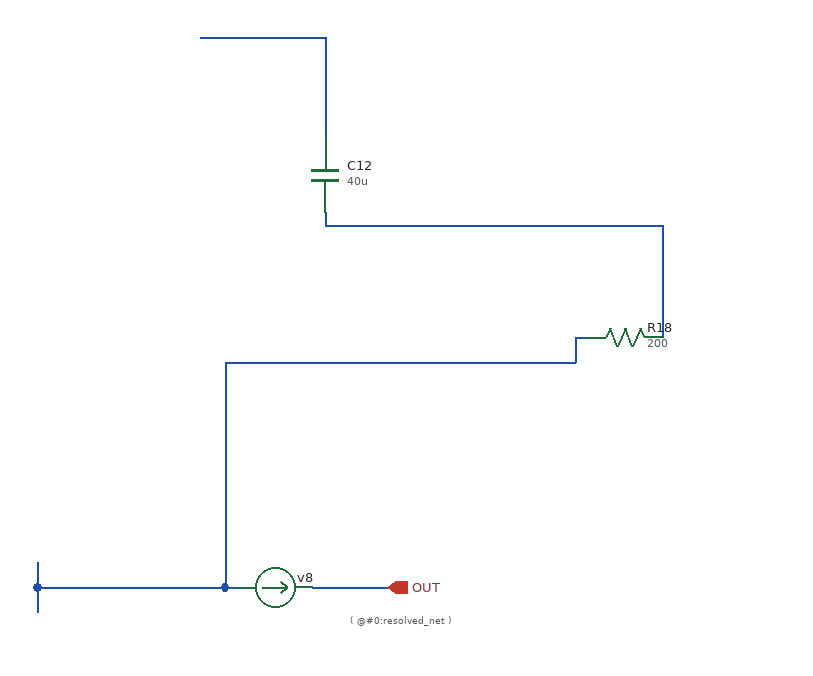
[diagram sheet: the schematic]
v {xschem version=3.4.8RC file_version=1.3}
G {}
K {}
V {}
S {}
F {}
E {}
T {( @#0:resolved_net )} -300 155 0 1 0.2 0.2 {name=p5 layer=15}
N -550 140 -550 160 {lab=#net1}
N -550 120 -550 140 {lab=#net1}
N -330 140 -270 140 {lab=OUT}
N -550 140 -400 140 {lab=#net1}
N -400 140 -390 140 {lab=#net1}
N -400 -40 -400 140 {lab=#net1}
N -50 -150 -50 -60 {lab=#net2}
N -320 -300 -320 -220 {lab=#net3}
N -420 -300 -320 -300 {lab=#net3}
N -320 -160 -320 -150 {lab=#net2}
N -320 -150 -50 -150 {lab=#net2}
N -400 -40 -120 -40 {lab=#net1}
N -120 -60 -110 -60 {lab=#net1}
N -120 -60 -120 -40 {lab=#net1}
C {devices/capa} -320 -190 0 0 {name=C12 m=1 value="40u"}
C {devices/res} -80 -60 1 1 {name=R18 m=1 value=200}
C {devices/ammeter} -360 140 3 0 {name=v8}
C {devices/opin} -270 140 0 0 {name=p5 lab=OUT}
